VERSION 5.7 ;
  NOWIREEXTENSIONATPIN ON ;
  DIVIDERCHAR "/" ;
  BUSBITCHARS "[]" ;
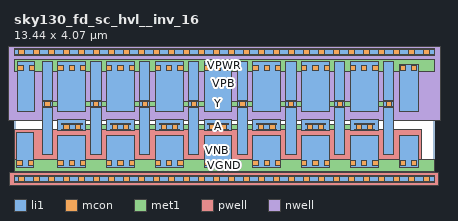
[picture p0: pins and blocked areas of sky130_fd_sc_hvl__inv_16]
MACRO sky130_fd_sc_hvl__inv_16
  CLASS BLOCK ;
  FOREIGN sky130_fd_sc_hvl__inv_16 ;
  ORIGIN 0.000 0.000 ;
  SIZE 13.440 BY 4.070 ;
  PIN A
    ANTENNAGATEAREA 18.000000 ;
    PORT
      LAYER li1 ;
        RECT 1.400 1.565 2.290 1.895 ;
        RECT 2.960 1.565 3.850 1.895 ;
        RECT 4.520 1.565 5.410 1.895 ;
        RECT 6.080 1.565 6.970 1.895 ;
        RECT 7.640 1.565 8.530 1.895 ;
        RECT 9.200 1.565 10.090 1.895 ;
        RECT 10.760 1.565 11.650 1.895 ;
      LAYER mcon ;
        RECT 1.595 1.580 1.765 1.750 ;
        RECT 1.955 1.580 2.125 1.750 ;
        RECT 3.145 1.580 3.315 1.750 ;
        RECT 3.505 1.580 3.675 1.750 ;
        RECT 4.705 1.580 4.875 1.750 ;
        RECT 5.065 1.580 5.235 1.750 ;
        RECT 6.265 1.580 6.435 1.750 ;
        RECT 6.625 1.580 6.795 1.750 ;
        RECT 7.825 1.580 7.995 1.750 ;
        RECT 8.185 1.580 8.355 1.750 ;
        RECT 9.385 1.580 9.555 1.750 ;
        RECT 9.745 1.580 9.915 1.750 ;
        RECT 10.945 1.580 11.115 1.750 ;
        RECT 11.305 1.580 11.475 1.750 ;
      LAYER met1 ;
        RECT 1.535 1.750 2.185 1.780 ;
        RECT 3.085 1.750 3.735 1.780 ;
        RECT 4.645 1.750 5.295 1.780 ;
        RECT 6.205 1.750 6.855 1.780 ;
        RECT 7.765 1.750 8.415 1.780 ;
        RECT 9.325 1.750 9.975 1.780 ;
        RECT 10.885 1.750 11.535 1.780 ;
        RECT 1.535 1.580 11.535 1.750 ;
        RECT 1.535 1.550 2.185 1.580 ;
        RECT 3.085 1.550 3.735 1.580 ;
        RECT 4.645 1.550 5.295 1.580 ;
        RECT 6.205 1.550 6.855 1.580 ;
        RECT 7.765 1.550 8.415 1.580 ;
        RECT 9.325 1.550 9.975 1.580 ;
        RECT 10.885 1.550 11.535 1.580 ;
    END
  END A
  PIN VGND
    USE GROUND ;
    PORT
      LAYER li1 ;
        RECT 0.095 0.375 0.630 1.475 ;
        RECT 1.400 0.375 2.290 1.395 ;
        RECT 2.960 0.375 3.850 1.395 ;
        RECT 4.520 0.375 5.410 1.395 ;
        RECT 6.080 0.375 6.970 1.395 ;
        RECT 7.640 0.375 8.530 1.395 ;
        RECT 9.200 0.375 10.090 1.395 ;
        RECT 10.760 0.375 11.650 1.395 ;
        RECT 12.320 0.375 12.935 1.395 ;
      LAYER mcon ;
        RECT 0.095 0.425 0.265 0.595 ;
        RECT 0.455 0.425 0.625 0.595 ;
        RECT 1.400 0.425 1.570 0.595 ;
        RECT 1.760 0.425 1.930 0.595 ;
        RECT 2.120 0.425 2.290 0.595 ;
        RECT 2.960 0.425 3.130 0.595 ;
        RECT 3.320 0.425 3.490 0.595 ;
        RECT 3.680 0.425 3.850 0.595 ;
        RECT 4.520 0.425 4.690 0.595 ;
        RECT 4.880 0.425 5.050 0.595 ;
        RECT 5.240 0.425 5.410 0.595 ;
        RECT 6.080 0.425 6.250 0.595 ;
        RECT 6.440 0.425 6.610 0.595 ;
        RECT 6.800 0.425 6.970 0.595 ;
        RECT 7.640 0.425 7.810 0.595 ;
        RECT 8.000 0.425 8.170 0.595 ;
        RECT 8.360 0.425 8.530 0.595 ;
        RECT 9.200 0.425 9.370 0.595 ;
        RECT 9.560 0.425 9.730 0.595 ;
        RECT 9.920 0.425 10.090 0.595 ;
        RECT 10.760 0.425 10.930 0.595 ;
        RECT 11.120 0.425 11.290 0.595 ;
        RECT 11.480 0.425 11.650 0.595 ;
        RECT 12.365 0.425 12.535 0.595 ;
        RECT 12.725 0.425 12.895 0.595 ;
      LAYER met1 ;
        RECT 0.000 0.255 13.440 0.625 ;
    END
  END VGND
  PIN VNB
    ANTENNADIFFAREA 2.284800 ;
    PORT
      LAYER pwell ;
        RECT 0.030 0.215 13.025 1.585 ;
        RECT -0.130 -0.215 13.570 0.215 ;
      LAYER li1 ;
        RECT 0.000 -0.085 13.440 0.085 ;
      LAYER mcon ;
        RECT 0.155 -0.085 0.325 0.085 ;
        RECT 0.635 -0.085 0.805 0.085 ;
        RECT 1.115 -0.085 1.285 0.085 ;
        RECT 1.595 -0.085 1.765 0.085 ;
        RECT 2.075 -0.085 2.245 0.085 ;
        RECT 2.555 -0.085 2.725 0.085 ;
        RECT 3.035 -0.085 3.205 0.085 ;
        RECT 3.515 -0.085 3.685 0.085 ;
        RECT 3.995 -0.085 4.165 0.085 ;
        RECT 4.475 -0.085 4.645 0.085 ;
        RECT 4.955 -0.085 5.125 0.085 ;
        RECT 5.435 -0.085 5.605 0.085 ;
        RECT 5.915 -0.085 6.085 0.085 ;
        RECT 6.395 -0.085 6.565 0.085 ;
        RECT 6.875 -0.085 7.045 0.085 ;
        RECT 7.355 -0.085 7.525 0.085 ;
        RECT 7.835 -0.085 8.005 0.085 ;
        RECT 8.315 -0.085 8.485 0.085 ;
        RECT 8.795 -0.085 8.965 0.085 ;
        RECT 9.275 -0.085 9.445 0.085 ;
        RECT 9.755 -0.085 9.925 0.085 ;
        RECT 10.235 -0.085 10.405 0.085 ;
        RECT 10.715 -0.085 10.885 0.085 ;
        RECT 11.195 -0.085 11.365 0.085 ;
        RECT 11.675 -0.085 11.845 0.085 ;
        RECT 12.155 -0.085 12.325 0.085 ;
        RECT 12.635 -0.085 12.805 0.085 ;
        RECT 13.115 -0.085 13.285 0.085 ;
      LAYER met1 ;
        RECT 0.000 -0.115 13.440 0.115 ;
    END
  END VNB
  PIN VPB
    ANTENNADIFFAREA 2.284800 ;
    PORT
      LAYER nwell ;
        RECT -0.330 1.885 13.770 4.485 ;
      LAYER li1 ;
        RECT 0.000 3.985 13.440 4.155 ;
      LAYER mcon ;
        RECT 0.155 3.985 0.325 4.155 ;
        RECT 0.635 3.985 0.805 4.155 ;
        RECT 1.115 3.985 1.285 4.155 ;
        RECT 1.595 3.985 1.765 4.155 ;
        RECT 2.075 3.985 2.245 4.155 ;
        RECT 2.555 3.985 2.725 4.155 ;
        RECT 3.035 3.985 3.205 4.155 ;
        RECT 3.515 3.985 3.685 4.155 ;
        RECT 3.995 3.985 4.165 4.155 ;
        RECT 4.475 3.985 4.645 4.155 ;
        RECT 4.955 3.985 5.125 4.155 ;
        RECT 5.435 3.985 5.605 4.155 ;
        RECT 5.915 3.985 6.085 4.155 ;
        RECT 6.395 3.985 6.565 4.155 ;
        RECT 6.875 3.985 7.045 4.155 ;
        RECT 7.355 3.985 7.525 4.155 ;
        RECT 7.835 3.985 8.005 4.155 ;
        RECT 8.315 3.985 8.485 4.155 ;
        RECT 8.795 3.985 8.965 4.155 ;
        RECT 9.275 3.985 9.445 4.155 ;
        RECT 9.755 3.985 9.925 4.155 ;
        RECT 10.235 3.985 10.405 4.155 ;
        RECT 10.715 3.985 10.885 4.155 ;
        RECT 11.195 3.985 11.365 4.155 ;
        RECT 11.675 3.985 11.845 4.155 ;
        RECT 12.155 3.985 12.325 4.155 ;
        RECT 12.635 3.985 12.805 4.155 ;
        RECT 13.115 3.985 13.285 4.155 ;
      LAYER met1 ;
        RECT 0.000 3.955 13.440 4.185 ;
    END
  END VPB
  PIN VPWR
    USE POWER ;
    PORT
      LAYER li1 ;
        RECT 0.125 2.175 0.655 3.755 ;
        RECT 1.400 2.175 2.290 3.755 ;
        RECT 2.960 2.175 3.850 3.755 ;
        RECT 4.520 2.175 5.410 3.755 ;
        RECT 6.080 2.175 6.970 3.755 ;
        RECT 7.640 2.175 8.530 3.755 ;
        RECT 9.200 2.175 10.090 3.755 ;
        RECT 10.760 2.175 11.650 3.755 ;
        RECT 12.320 2.175 12.935 3.675 ;
      LAYER mcon ;
        RECT 0.125 3.475 0.295 3.645 ;
        RECT 0.485 3.475 0.655 3.645 ;
        RECT 1.400 3.475 1.570 3.645 ;
        RECT 1.760 3.475 1.930 3.645 ;
        RECT 2.120 3.475 2.290 3.645 ;
        RECT 2.960 3.475 3.130 3.645 ;
        RECT 3.320 3.475 3.490 3.645 ;
        RECT 3.680 3.475 3.850 3.645 ;
        RECT 4.520 3.475 4.690 3.645 ;
        RECT 4.880 3.475 5.050 3.645 ;
        RECT 5.240 3.475 5.410 3.645 ;
        RECT 6.080 3.475 6.250 3.645 ;
        RECT 6.440 3.475 6.610 3.645 ;
        RECT 6.800 3.475 6.970 3.645 ;
        RECT 7.640 3.475 7.810 3.645 ;
        RECT 8.000 3.475 8.170 3.645 ;
        RECT 8.360 3.475 8.530 3.645 ;
        RECT 9.200 3.475 9.370 3.645 ;
        RECT 9.560 3.475 9.730 3.645 ;
        RECT 9.920 3.475 10.090 3.645 ;
        RECT 10.760 3.475 10.930 3.645 ;
        RECT 11.120 3.475 11.290 3.645 ;
        RECT 11.480 3.475 11.650 3.645 ;
        RECT 12.365 3.475 12.535 3.645 ;
        RECT 12.725 3.475 12.895 3.645 ;
      LAYER met1 ;
        RECT 0.000 3.445 13.440 3.815 ;
    END
  END VPWR
  PIN Y
    ANTENNADIFFAREA 5.040000 ;
    PORT
      LAYER li1 ;
        RECT 0.900 0.795 1.230 3.755 ;
        RECT 2.460 0.795 2.790 3.755 ;
        RECT 4.020 0.795 4.350 3.755 ;
        RECT 5.580 0.795 5.910 3.755 ;
        RECT 7.140 0.795 7.470 3.755 ;
        RECT 8.700 0.795 9.030 3.755 ;
        RECT 10.260 0.795 10.590 3.755 ;
        RECT 11.820 0.795 12.150 3.755 ;
      LAYER mcon ;
        RECT 0.985 2.320 1.155 2.490 ;
        RECT 2.545 2.320 2.715 2.490 ;
        RECT 4.105 2.320 4.275 2.490 ;
        RECT 5.665 2.320 5.835 2.490 ;
        RECT 7.225 2.320 7.395 2.490 ;
        RECT 8.785 2.320 8.955 2.490 ;
        RECT 10.345 2.320 10.515 2.490 ;
        RECT 11.905 2.320 12.075 2.490 ;
      LAYER met1 ;
        RECT 0.925 2.490 1.215 2.520 ;
        RECT 2.485 2.490 2.775 2.520 ;
        RECT 4.045 2.490 4.335 2.520 ;
        RECT 5.605 2.490 5.895 2.520 ;
        RECT 7.165 2.490 7.455 2.520 ;
        RECT 8.725 2.490 9.015 2.520 ;
        RECT 10.285 2.490 10.575 2.520 ;
        RECT 11.845 2.490 12.135 2.520 ;
        RECT 0.925 2.320 12.135 2.490 ;
        RECT 0.925 2.290 1.215 2.320 ;
        RECT 2.485 2.290 2.775 2.320 ;
        RECT 4.045 2.290 4.335 2.320 ;
        RECT 5.605 2.290 5.895 2.320 ;
        RECT 7.165 2.290 7.455 2.320 ;
        RECT 8.725 2.290 9.015 2.320 ;
        RECT 10.285 2.290 10.575 2.320 ;
        RECT 11.845 2.290 12.135 2.320 ;
    END
  END Y
END sky130_fd_sc_hvl__inv_16
END LIBRARY

